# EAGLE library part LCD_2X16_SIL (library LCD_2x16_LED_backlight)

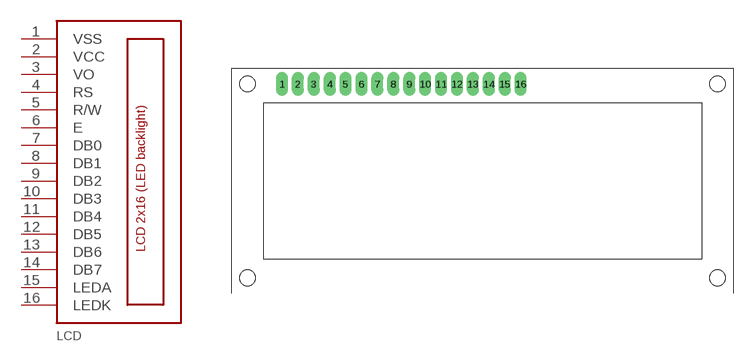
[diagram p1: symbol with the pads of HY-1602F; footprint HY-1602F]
Designator prefix LCD

## LCD_2X16_SIL  [HY-1602F]
1  VSS  pwr
2  VCC  pwr
3  VO  in
4  RS  in
5  R/W  in
6  E  in
7  DB0
8  DB1
9  DB2
10  DB3
11  DB4
12  DB5
13  DB6
14  DB7
15  LEDA  pas
16  LEDK  pas

## Footprint HY-1602F (pad centres in mm)
drill 1 pad 1.93 long: 1 2.54,0; 2 5.08,0; 3 7.62,0; 4 10.16,0; 5 12.7,0; 6 15.24,0; 7 17.78,0; 8 20.32,0; 9 22.86,0; 10 25.4,0; 11 27.94,0; 12 30.48,0; 13 33.02,0; 14 35.56,0; 15 38.1,0; 16 40.64,0
hole 2.5 at -2.96,0
hole 2.5 at 72.04,0
hole 2.5 at -2.96,-31
hole 2.5 at 72.04,-31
